VERSION 5.7 ;
  NOWIREEXTENSIONATPIN ON ;
  DIVIDERCHAR "/" ;
  BUSBITCHARS "[]" ;
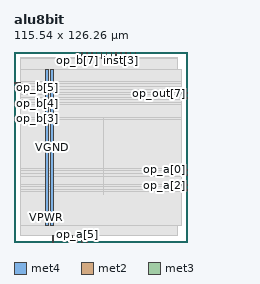
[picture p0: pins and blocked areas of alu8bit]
MACRO alu8bit
  CLASS BLOCK ;
  FOREIGN alu8bit ;
  ORIGIN 0.000 0.000 ;
  SIZE 115.540 BY 126.260 ;
  PIN VGND
    DIRECTION INOUT ;
    USE GROUND ;
    PORT
      LAYER met4 ;
        RECT 24.340 10.640 25.940 114.480 ;
    END
  END VGND
  PIN VPWR
    DIRECTION INOUT ;
    USE POWER ;
    PORT
      LAYER met4 ;
        RECT 21.040 10.640 22.640 114.480 ;
    END
  END VPWR
  PIN inst[0]
    DIRECTION INPUT ;
    USE SIGNAL ;
    ANTENNAGATEAREA 0.126000 ;
    PORT
      LAYER met2 ;
        RECT 67.710 122.260 67.990 126.260 ;
    END
  END inst[0]
  PIN inst[1]
    DIRECTION INPUT ;
    USE SIGNAL ;
    ANTENNAGATEAREA 0.126000 ;
    PORT
      LAYER met2 ;
        RECT 58.050 122.260 58.330 126.260 ;
    END
  END inst[1]
  PIN inst[2]
    DIRECTION INPUT ;
    USE SIGNAL ;
    ANTENNAGATEAREA 0.159000 ;
    PORT
      LAYER met2 ;
        RECT 74.150 122.260 74.430 126.260 ;
    END
  END inst[2]
  PIN inst[3]
    DIRECTION INPUT ;
    USE SIGNAL ;
    ANTENNAGATEAREA 0.159000 ;
    PORT
      LAYER met2 ;
        RECT 70.930 122.260 71.210 126.260 ;
    END
  END inst[3]
  PIN op_a[0]
    DIRECTION INPUT ;
    USE SIGNAL ;
    ANTENNAGATEAREA 0.213000 ;
    PORT
      LAYER met3 ;
        RECT 111.540 47.640 115.540 48.240 ;
    END
  END op_a[0]
  PIN op_a[1]
    DIRECTION INPUT ;
    USE SIGNAL ;
    ANTENNAGATEAREA 0.159000 ;
    PORT
      LAYER met3 ;
        RECT 111.540 44.240 115.540 44.840 ;
    END
  END op_a[1]
  PIN op_a[2]
    DIRECTION INPUT ;
    USE SIGNAL ;
    ANTENNAGATEAREA 0.213000 ;
    PORT
      LAYER met3 ;
        RECT 111.540 37.440 115.540 38.040 ;
    END
  END op_a[2]
  PIN op_a[3]
    DIRECTION INPUT ;
    USE SIGNAL ;
    ANTENNAGATEAREA 0.247500 ;
    PORT
      LAYER met3 ;
        RECT 111.540 34.040 115.540 34.640 ;
    END
  END op_a[3]
  PIN op_a[4]
    DIRECTION INPUT ;
    USE SIGNAL ;
    ANTENNAGATEAREA 0.213000 ;
    PORT
      LAYER met2 ;
        RECT 45.170 0.000 45.450 4.000 ;
    END
  END op_a[4]
  PIN op_a[5]
    DIRECTION INPUT ;
    USE SIGNAL ;
    ANTENNAGATEAREA 0.213000 ;
    PORT
      LAYER met2 ;
        RECT 41.950 0.000 42.230 4.000 ;
    END
  END op_a[5]
  PIN op_a[6]
    DIRECTION INPUT ;
    USE SIGNAL ;
    ANTENNAGATEAREA 0.247500 ;
    PORT
      LAYER met2 ;
        RECT 45.170 122.260 45.450 126.260 ;
    END
  END op_a[6]
  PIN op_a[7]
    DIRECTION INPUT ;
    USE SIGNAL ;
    ANTENNAGATEAREA 0.213000 ;
    PORT
      LAYER met2 ;
        RECT 77.370 122.260 77.650 126.260 ;
    END
  END op_a[7]
  PIN op_b[0]
    DIRECTION INPUT ;
    USE SIGNAL ;
    ANTENNAGATEAREA 0.159000 ;
    PORT
      LAYER met2 ;
        RECT 38.730 0.000 39.010 4.000 ;
    END
  END op_b[0]
  PIN op_b[1]
    DIRECTION INPUT ;
    USE SIGNAL ;
    ANTENNAGATEAREA 0.196500 ;
    PORT
      LAYER met2 ;
        RECT 48.390 0.000 48.670 4.000 ;
    END
  END op_b[1]
  PIN op_b[2]
    DIRECTION INPUT ;
    USE SIGNAL ;
    ANTENNAGATEAREA 0.159000 ;
    PORT
      LAYER met2 ;
        RECT 25.850 0.000 26.130 4.000 ;
    END
  END op_b[2]
  PIN op_b[3]
    DIRECTION INPUT ;
    USE SIGNAL ;
    ANTENNAGATEAREA 0.159000 ;
    PORT
      LAYER met3 ;
        RECT 0.000 81.640 4.000 82.240 ;
    END
  END op_b[3]
  PIN op_b[4]
    DIRECTION INPUT ;
    USE SIGNAL ;
    ANTENNAGATEAREA 0.159000 ;
    PORT
      LAYER met3 ;
        RECT 0.000 91.840 4.000 92.440 ;
    END
  END op_b[4]
  PIN op_b[5]
    DIRECTION INPUT ;
    USE SIGNAL ;
    ANTENNAGATEAREA 0.213000 ;
    PORT
      LAYER met3 ;
        RECT 0.000 102.040 4.000 102.640 ;
    END
  END op_b[5]
  PIN op_b[6]
    DIRECTION INPUT ;
    USE SIGNAL ;
    ANTENNAGATEAREA 0.126000 ;
    PORT
      LAYER met3 ;
        RECT 0.000 105.440 4.000 106.040 ;
    END
  END op_b[6]
  PIN op_b[7]
    DIRECTION INPUT ;
    USE SIGNAL ;
    ANTENNAGATEAREA 0.426000 ;
    PORT
      LAYER met2 ;
        RECT 41.950 122.260 42.230 126.260 ;
    END
  END op_b[7]
  PIN op_out[0]
    DIRECTION OUTPUT ;
    USE SIGNAL ;
    ANTENNADIFFAREA 0.340600 ;
    PORT
      LAYER met2 ;
        RECT 61.270 122.260 61.550 126.260 ;
    END
  END op_out[0]
  PIN op_out[1]
    DIRECTION OUTPUT ;
    USE SIGNAL ;
    ANTENNADIFFAREA 0.340600 ;
    PORT
      LAYER met2 ;
        RECT 64.490 122.260 64.770 126.260 ;
    END
  END op_out[1]
  PIN op_out[2]
    DIRECTION OUTPUT ;
    USE SIGNAL ;
    ANTENNADIFFAREA 0.340600 ;
    PORT
      LAYER met2 ;
        RECT 48.390 122.260 48.670 126.260 ;
    END
  END op_out[2]
  PIN op_out[3]
    DIRECTION OUTPUT ;
    USE SIGNAL ;
    ANTENNADIFFAREA 0.340600 ;
    PORT
      LAYER met2 ;
        RECT 54.830 122.260 55.110 126.260 ;
    END
  END op_out[3]
  PIN op_out[4]
    DIRECTION OUTPUT ;
    USE SIGNAL ;
    ANTENNADIFFAREA 0.340600 ;
    PORT
      LAYER met2 ;
        RECT 51.610 122.260 51.890 126.260 ;
    END
  END op_out[4]
  PIN op_out[5]
    DIRECTION OUTPUT ;
    USE SIGNAL ;
    ANTENNADIFFAREA 0.340600 ;
    PORT
      LAYER met2 ;
        RECT 80.590 122.260 80.870 126.260 ;
    END
  END op_out[5]
  PIN op_out[6]
    DIRECTION OUTPUT ;
    USE SIGNAL ;
    ANTENNADIFFAREA 0.340600 ;
    PORT
      LAYER met3 ;
        RECT 111.540 95.240 115.540 95.840 ;
    END
  END op_out[6]
  PIN op_out[7]
    DIRECTION OUTPUT ;
    USE SIGNAL ;
    ANTENNADIFFAREA 0.340600 ;
    PORT
      LAYER met3 ;
        RECT 111.540 98.640 115.540 99.240 ;
    END
  END op_out[7]
  OBS
      LAYER nwell ;
        RECT 5.330 10.795 110.130 114.325 ;
      LAYER li1 ;
        RECT 5.520 10.795 109.940 114.325 ;
      LAYER met1 ;
        RECT 4.210 10.640 109.940 114.480 ;
      LAYER met2 ;
        RECT 4.230 121.980 41.670 122.810 ;
        RECT 42.510 121.980 44.890 122.810 ;
        RECT 45.730 121.980 48.110 122.810 ;
        RECT 48.950 121.980 51.330 122.810 ;
        RECT 52.170 121.980 54.550 122.810 ;
        RECT 55.390 121.980 57.770 122.810 ;
        RECT 58.610 121.980 60.990 122.810 ;
        RECT 61.830 121.980 64.210 122.810 ;
        RECT 65.050 121.980 67.430 122.810 ;
        RECT 68.270 121.980 70.650 122.810 ;
        RECT 71.490 121.980 73.870 122.810 ;
        RECT 74.710 121.980 77.090 122.810 ;
        RECT 77.930 121.980 80.310 122.810 ;
        RECT 81.150 121.980 108.470 122.810 ;
        RECT 4.230 4.280 108.470 121.980 ;
        RECT 4.230 4.000 25.570 4.280 ;
        RECT 26.410 4.000 38.450 4.280 ;
        RECT 39.290 4.000 41.670 4.280 ;
        RECT 42.510 4.000 44.890 4.280 ;
        RECT 45.730 4.000 48.110 4.280 ;
        RECT 48.950 4.000 108.470 4.280 ;
      LAYER met3 ;
        RECT 3.990 106.440 111.540 114.405 ;
        RECT 4.400 105.040 111.540 106.440 ;
        RECT 3.990 103.040 111.540 105.040 ;
        RECT 4.400 101.640 111.540 103.040 ;
        RECT 3.990 99.640 111.540 101.640 ;
        RECT 3.990 98.240 111.140 99.640 ;
        RECT 3.990 96.240 111.540 98.240 ;
        RECT 3.990 94.840 111.140 96.240 ;
        RECT 3.990 92.840 111.540 94.840 ;
        RECT 4.400 91.440 111.540 92.840 ;
        RECT 3.990 82.640 111.540 91.440 ;
        RECT 4.400 81.240 111.540 82.640 ;
        RECT 3.990 48.640 111.540 81.240 ;
        RECT 3.990 47.240 111.140 48.640 ;
        RECT 3.990 45.240 111.540 47.240 ;
        RECT 3.990 43.840 111.140 45.240 ;
        RECT 3.990 38.440 111.540 43.840 ;
        RECT 3.990 37.040 111.140 38.440 ;
        RECT 3.990 35.040 111.540 37.040 ;
        RECT 3.990 33.640 111.140 35.040 ;
        RECT 3.990 10.715 111.540 33.640 ;
      LAYER met4 ;
        RECT 59.175 31.455 59.505 82.105 ;
  END
END alu8bit
END LIBRARY

